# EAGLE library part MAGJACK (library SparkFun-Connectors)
RJ-45 with LEDs

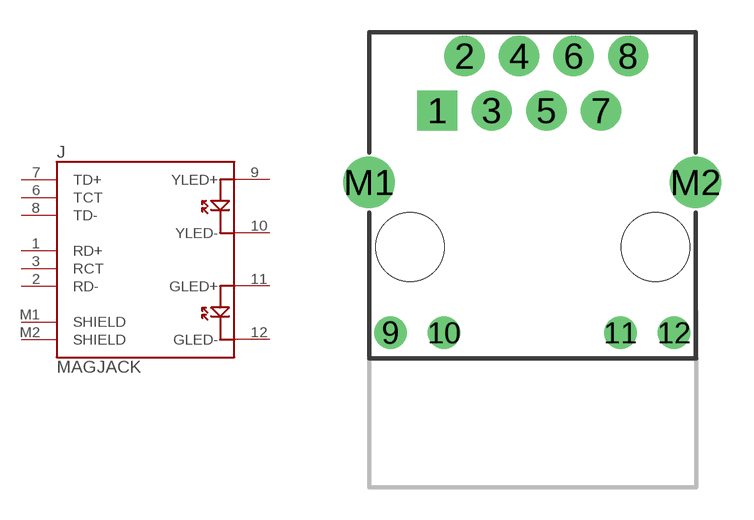
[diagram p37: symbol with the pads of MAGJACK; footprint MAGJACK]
Designator prefix J

## MAGJACK  [MAGJACK]
1  RD+
2  RD-
3  RCT
6  TCT
7  TD+
8  TD-
9  YLED+
10  YLED-
11  GLED+
12  GLED-
M1  SHIELD
M2  SHIELD

## Footprint MAGJACK (pad centres in mm)
drill 1 pad 1.88 square: 1 3.175,17.445
drill 1 pad 1.88: 2 4.445,19.985; 3 5.715,17.445; 4 6.985,19.985; 5 8.255,17.445; 6 9.525,19.985; 7 10.795,17.445; 8 12.065,19.985
drill 1 pad 1.27: 9 1,7.1; 10 3.5,7.1; 11 11.7,7.1; 12 14.2,7.1
drill 1.6 pad 2.184: M1 0,14.1; M2 15.2,14.1
hole 3.2 at 1.905,11.095
hole 3.2 at 13.335,11.095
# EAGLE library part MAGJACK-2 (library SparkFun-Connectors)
RJ-45 with LEDs

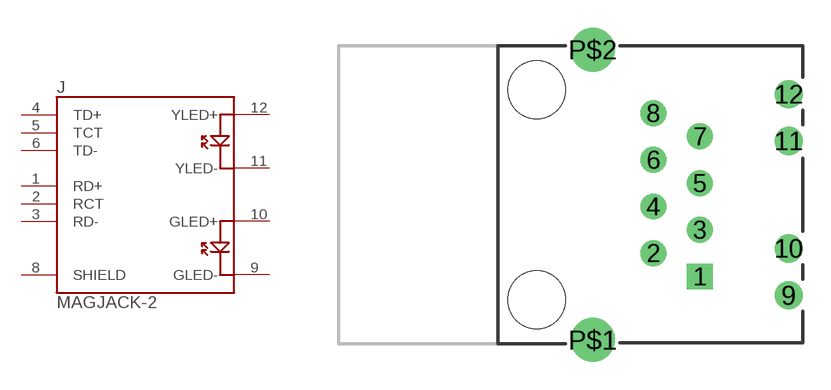
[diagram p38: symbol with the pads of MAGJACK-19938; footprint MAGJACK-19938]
Designator prefix J

## MAGJACK-2  [MAGJACK-19938]
1  RD+
2  RCT
3  RD-
4  TD+
5  TCT
6  TD-
8  SHIELD
9  GLED-
10  GLED+
11  YLED-
12  YLED+

## Footprint MAGJACK-19938 (pad centres in mm)
drill 0.9 square: 1 0,0
drill 0.9: 2 -2.54,1.27; 3 0,2.54; 4 -2.54,3.81; 5 0,5.08; 6 -2.54,6.35; 7 0,7.62; 8 -2.54,8.89
drill 1.02: 9 4.83,-1.02; 10 4.83,1.52; 11 4.83,7.37; 12 4.83,9.91
drill 1.6: P$1 -5.84,-3.455; P$2 -5.84,12.345
hole 3.15 at -8.89,-1.27
hole 3.15 at -8.89,10.16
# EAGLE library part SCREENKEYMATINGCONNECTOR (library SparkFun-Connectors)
ScreenKey mating connector- PRT-09586

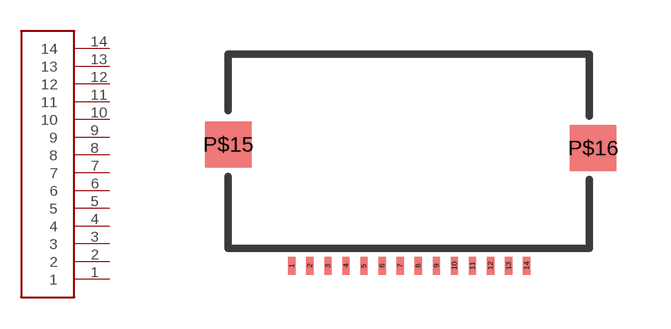
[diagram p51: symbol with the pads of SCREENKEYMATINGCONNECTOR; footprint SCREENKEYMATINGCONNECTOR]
Designator prefix -

## SCREENKEYMATINGCONNECTOR  [SCREENKEYMATINGCONNECTOR]
1  1
2  2
3  3
4  4
5  5
6  6
7  7
8  8
9  9
10  10
11  11
12  12
13  13
14  14

## Footprint SCREENKEYMATINGCONNECTOR (pad centres in mm)
smd 0.2 x 0.5: 1 1.76,-0.36; 2 2.26,-0.36; 3 2.76,-0.36; 4 3.26,-0.36; 5 3.76,-0.36; 6 4.26,-0.36; 7 4.76,-0.36; 8 5.26,-0.36; 9 5.76,-0.36; 10 6.26,-0.36; 11 6.76,-0.36; 12 7.26,-0.36; 13 7.76,-0.36; 14 8.26,-0.36
smd 1.28 x 1.28: P$15 0,3; P$16 10.1,2.9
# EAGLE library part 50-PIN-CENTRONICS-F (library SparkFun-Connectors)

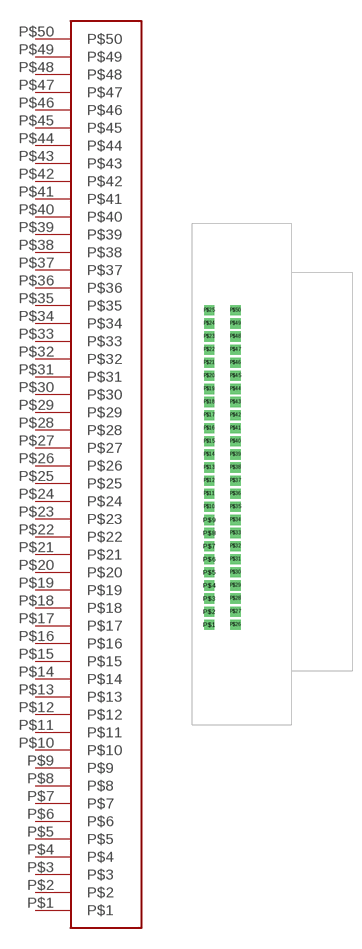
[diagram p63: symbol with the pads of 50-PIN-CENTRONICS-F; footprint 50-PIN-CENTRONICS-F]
Designator prefix -

## 50-PIN-CENTRONICS-FFEMALE  [50-PIN-CENTRONICS-F]
P$1  P$1
P$2  P$2
P$3  P$3
P$4  P$4
P$5  P$5
P$6  P$6
P$7  P$7
P$8  P$8
P$9  P$9
P$10  P$10
P$11  P$11
P$12  P$12
P$13  P$13
P$14  P$14
P$15  P$15
P$16  P$16
P$17  P$17
P$18  P$18
P$19  P$19
P$20  P$20
P$21  P$21
P$22  P$22
P$23  P$23
P$24  P$24
P$25  P$25
P$26  P$26
P$27  P$27
P$28  P$28
P$29  P$29
P$30  P$30
P$31  P$31
P$32  P$32
P$33  P$33
P$34  P$34
P$35  P$35
P$36  P$36
P$37  P$37
P$38  P$38
P$39  P$39
P$40  P$40
P$41  P$41
P$42  P$42
P$43  P$43
P$44  P$44
P$45  P$45
P$46  P$46
P$47  P$47
P$48  P$48
P$49  P$49
P$50  P$50

## Footprint 50-PIN-CENTRONICS-F (pad centres in mm)
drill 0.9 pad 1.676 square: P$1 0,0; P$2 0,2.159; P$3 0,4.318; P$4 0,6.477; P$5 0,8.636; P$6 0,10.795; P$7 0,12.954; P$8 0,15.113; P$9 0,17.272; P$10 0,19.431; P$11 0,21.59; P$12 0,23.749; P$13 0,25.908; P$14 0,28.067; P$15 0,30.226; P$16 0,32.385; P$17 0,34.544; P$18 0,36.703; P$19 0,38.862; P$20 0,41.021; P$21 0,43.18; P$22 0,45.339; P$23 0,47.498; P$24 0,49.657; P$25 0,51.816; P$26 4.318,0; P$27 4.318,2.159; P$28 4.318,4.318; P$29 4.318,6.477; P$30 4.318,8.636; P$31 4.318,10.795; P$32 4.318,12.954; P$33 4.318,15.113; P$34 4.318,17.272; P$35 4.318,19.431; P$36 4.318,21.59; P$37 4.318,23.749; P$38 4.318,25.908; P$39 4.318,28.067; P$40 4.318,30.226; P$41 4.318,32.385; P$42 4.318,34.544; P$43 4.318,36.703; P$44 4.318,38.862; P$45 4.318,41.021; P$46 4.318,43.18; P$47 4.318,45.339; P$48 4.318,47.498; P$49 4.318,49.657; P$50 4.318,51.816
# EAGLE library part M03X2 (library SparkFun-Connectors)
Shrouded 2x3 .1" header, with keying.

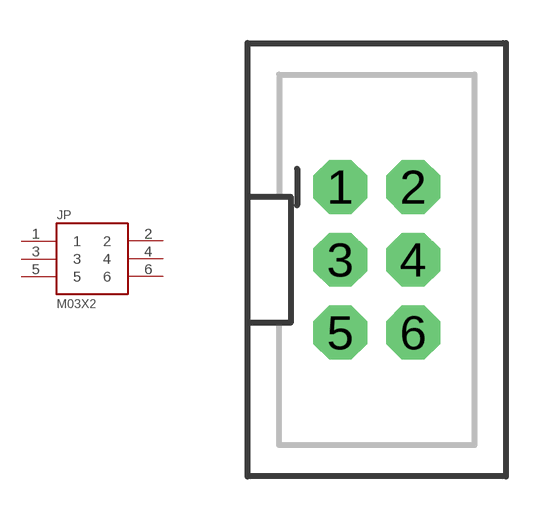
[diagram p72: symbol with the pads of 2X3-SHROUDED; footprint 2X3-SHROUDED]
Designator prefix JP

## M03X2  [2X3-SHROUDED]
1  1
2  2
3  3
4  4
5  5
6  6

## Footprint 2X3-SHROUDED (pad centres in mm)
drill 1.016 pad 1.88 octagon: 1 -1.27,2.54; 2 1.27,2.54; 3 -1.27,0; 4 1.27,0; 5 -1.27,-2.54; 6 1.27,-2.54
